# Generated by innovus_enablement/scripts/gen_fakeram.py: abstract 64x7 SRAM.
# Geometry is an assumption (see script header), not PDK data.
VERSION 5.8 ;
BUSBITCHARS "[]" ;
DIVIDERCHAR "/" ;

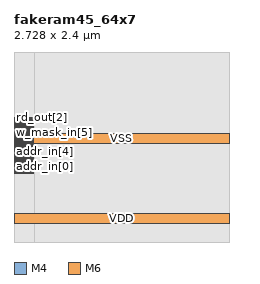
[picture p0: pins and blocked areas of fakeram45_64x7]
MACRO fakeram45_64x7
  CLASS BLOCK ;
  FOREIGN fakeram45_64x7 0 0 ;
  ORIGIN 0 0 ;
  SIZE 2.7280 BY 2.4000 ;
  SYMMETRY X Y R90 ;
  PIN clk
    DIRECTION INPUT ;
    USE CLOCK ;
    PORT
      LAYER M4 ;
        RECT 0 0.8700 0.2400 0.8820 ;
    END
  END clk
  PIN ce_in
    DIRECTION INPUT ;
    USE SIGNAL ;
    PORT
      LAYER M4 ;
        RECT 0 0.8940 0.2400 0.9060 ;
    END
  END ce_in
  PIN we_in
    DIRECTION INPUT ;
    USE SIGNAL ;
    PORT
      LAYER M4 ;
        RECT 0 0.9180 0.2400 0.9300 ;
    END
  END we_in
  PIN addr_in[0]
    DIRECTION INPUT ;
    USE SIGNAL ;
    PORT
      LAYER M4 ;
        RECT 0 0.9420 0.2400 0.9540 ;
    END
  END addr_in[0]
  PIN addr_in[1]
    DIRECTION INPUT ;
    USE SIGNAL ;
    PORT
      LAYER M4 ;
        RECT 0 0.9660 0.2400 0.9780 ;
    END
  END addr_in[1]
  PIN addr_in[2]
    DIRECTION INPUT ;
    USE SIGNAL ;
    PORT
      LAYER M4 ;
        RECT 0 0.9900 0.2400 1.0020 ;
    END
  END addr_in[2]
  PIN addr_in[3]
    DIRECTION INPUT ;
    USE SIGNAL ;
    PORT
      LAYER M4 ;
        RECT 0 1.0140 0.2400 1.0260 ;
    END
  END addr_in[3]
  PIN addr_in[4]
    DIRECTION INPUT ;
    USE SIGNAL ;
    PORT
      LAYER M4 ;
        RECT 0 1.0380 0.2400 1.0500 ;
    END
  END addr_in[4]
  PIN addr_in[5]
    DIRECTION INPUT ;
    USE SIGNAL ;
    PORT
      LAYER M4 ;
        RECT 0 1.0620 0.2400 1.0740 ;
    END
  END addr_in[5]
  PIN wd_in[0]
    DIRECTION INPUT ;
    USE SIGNAL ;
    PORT
      LAYER M4 ;
        RECT 0 1.0860 0.2400 1.0980 ;
    END
  END wd_in[0]
  PIN wd_in[1]
    DIRECTION INPUT ;
    USE SIGNAL ;
    PORT
      LAYER M4 ;
        RECT 0 1.1100 0.2400 1.1220 ;
    END
  END wd_in[1]
  PIN wd_in[2]
    DIRECTION INPUT ;
    USE SIGNAL ;
    PORT
      LAYER M4 ;
        RECT 0 1.1340 0.2400 1.1460 ;
    END
  END wd_in[2]
  PIN wd_in[3]
    DIRECTION INPUT ;
    USE SIGNAL ;
    PORT
      LAYER M4 ;
        RECT 0 1.1580 0.2400 1.1700 ;
    END
  END wd_in[3]
  PIN wd_in[4]
    DIRECTION INPUT ;
    USE SIGNAL ;
    PORT
      LAYER M4 ;
        RECT 0 1.1820 0.2400 1.1940 ;
    END
  END wd_in[4]
  PIN wd_in[5]
    DIRECTION INPUT ;
    USE SIGNAL ;
    PORT
      LAYER M4 ;
        RECT 0 1.2060 0.2400 1.2180 ;
    END
  END wd_in[5]
  PIN wd_in[6]
    DIRECTION INPUT ;
    USE SIGNAL ;
    PORT
      LAYER M4 ;
        RECT 0 1.2300 0.2400 1.2420 ;
    END
  END wd_in[6]
  PIN w_mask_in[0]
    DIRECTION INPUT ;
    USE SIGNAL ;
    PORT
      LAYER M4 ;
        RECT 0 1.2540 0.2400 1.2660 ;
    END
  END w_mask_in[0]
  PIN w_mask_in[1]
    DIRECTION INPUT ;
    USE SIGNAL ;
    PORT
      LAYER M4 ;
        RECT 0 1.2780 0.2400 1.2900 ;
    END
  END w_mask_in[1]
  PIN w_mask_in[2]
    DIRECTION INPUT ;
    USE SIGNAL ;
    PORT
      LAYER M4 ;
        RECT 0 1.3020 0.2400 1.3140 ;
    END
  END w_mask_in[2]
  PIN w_mask_in[3]
    DIRECTION INPUT ;
    USE SIGNAL ;
    PORT
      LAYER M4 ;
        RECT 0 1.3260 0.2400 1.3380 ;
    END
  END w_mask_in[3]
  PIN w_mask_in[4]
    DIRECTION INPUT ;
    USE SIGNAL ;
    PORT
      LAYER M4 ;
        RECT 0 1.3500 0.2400 1.3620 ;
    END
  END w_mask_in[4]
  PIN w_mask_in[5]
    DIRECTION INPUT ;
    USE SIGNAL ;
    PORT
      LAYER M4 ;
        RECT 0 1.3740 0.2400 1.3860 ;
    END
  END w_mask_in[5]
  PIN w_mask_in[6]
    DIRECTION INPUT ;
    USE SIGNAL ;
    PORT
      LAYER M4 ;
        RECT 0 1.3980 0.2400 1.4100 ;
    END
  END w_mask_in[6]
  PIN rd_out[0]
    DIRECTION OUTPUT ;
    USE SIGNAL ;
    PORT
      LAYER M4 ;
        RECT 0 1.4220 0.2400 1.4340 ;
    END
  END rd_out[0]
  PIN rd_out[1]
    DIRECTION OUTPUT ;
    USE SIGNAL ;
    PORT
      LAYER M4 ;
        RECT 0 1.4460 0.2400 1.4580 ;
    END
  END rd_out[1]
  PIN rd_out[2]
    DIRECTION OUTPUT ;
    USE SIGNAL ;
    PORT
      LAYER M4 ;
        RECT 0 1.4700 0.2400 1.4820 ;
    END
  END rd_out[2]
  PIN rd_out[3]
    DIRECTION OUTPUT ;
    USE SIGNAL ;
    PORT
      LAYER M4 ;
        RECT 0 1.4940 0.2400 1.5060 ;
    END
  END rd_out[3]
  PIN rd_out[4]
    DIRECTION OUTPUT ;
    USE SIGNAL ;
    PORT
      LAYER M4 ;
        RECT 0 1.5180 0.2400 1.5300 ;
    END
  END rd_out[4]
  PIN rd_out[5]
    DIRECTION OUTPUT ;
    USE SIGNAL ;
    PORT
      LAYER M4 ;
        RECT 0 1.5420 0.2400 1.5540 ;
    END
  END rd_out[5]
  PIN rd_out[6]
    DIRECTION OUTPUT ;
    USE SIGNAL ;
    PORT
      LAYER M4 ;
        RECT 0 1.5660 0.2400 1.5780 ;
    END
  END rd_out[6]
  PIN VDD
    DIRECTION INOUT ;
    USE POWER ;
    PORT
      LAYER M6 ;
        RECT 0 0.2400 2.7280 0.3600 ;
    END
  END VDD
  PIN VSS
    DIRECTION INOUT ;
    USE GROUND ;
    PORT
      LAYER M6 ;
        RECT 0 1.2480 2.7280 1.3680 ;
    END
  END VSS
  OBS
    LAYER M0 ;
      RECT 0 0 2.7280 2.4000 ;
    LAYER M1 ;
      RECT 0 0 2.7280 2.4000 ;
    LAYER M2 ;
      RECT 0 0 2.7280 2.4000 ;
    LAYER M3 ;
      RECT 0 0 2.7280 2.4000 ;
    LAYER VIA0 ;
      RECT 0 0 2.7280 2.4000 ;
    LAYER VIA1 ;
      RECT 0 0 2.7280 2.4000 ;
    LAYER VIA2 ;
      RECT 0 0 2.7280 2.4000 ;
    LAYER VIA3 ;
      RECT 0 0 2.7280 2.4000 ;
    LAYER M4 ;
      RECT 0.2640 0 2.7280 2.4000 ;
  END
END fakeram45_64x7

END LIBRARY
